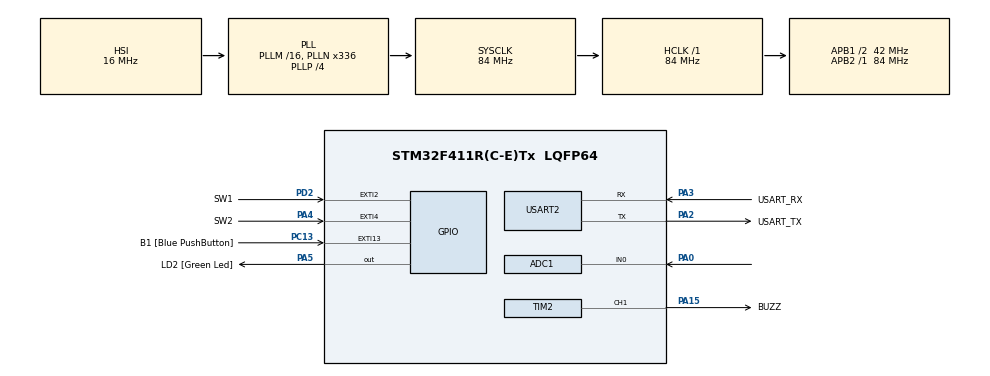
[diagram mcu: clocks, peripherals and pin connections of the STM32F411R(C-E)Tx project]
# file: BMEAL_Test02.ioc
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ADC1.Channel-3\#ChannelRegularConversion=ADC_CHANNEL_0
ADC1.Channel-5\#ChannelRegularConversion=ADC_CHANNEL_TEMPSENSOR
ADC1.EnableAnalogWatchDog=false
ADC1.NbrOfConversion=2
ADC1.NbrOfConversionFlag=1
ADC1.Rank-3\#ChannelRegularConversion=1
ADC1.Rank-5\#ChannelRegularConversion=2
ADC1.SamplingTime-3\#ChannelRegularConversion=ADC_SAMPLETIME_112CYCLES
ADC1.SamplingTime-5\#ChannelRegularConversion=ADC_SAMPLETIME_112CYCLES
ADC1.ScanConvMode=ENABLE
ADC1.master=1
Mcu.Family=STM32F4
Mcu.Name=STM32F411R(C-E)Tx
Mcu.Package=LQFP64
NVIC.EXTI2_IRQn=true\:0\:0\:false\:false\:true\:true\:true\:true
NVIC.EXTI4_IRQn=true\:0\:0\:false\:false\:true\:true\:true\:true
NVIC.PriorityGroup=NVIC_PRIORITYGROUP_0
PA0-WKUP.Signal=ADCx_IN0
PA13.GPIO_Label=TMS
PA13.Mode=Serial_Wire
PA13.Signal=SYS_JTMS-SWDIO
PA14.GPIO_Label=TCK
PA14.Mode=Serial_Wire
PA14.Signal=SYS_JTCK-SWCLK
PA15.GPIO_Label=BUZZ
PA15.Signal=S_TIM2_CH1_ETR
PA2.GPIO_Label=USART_TX
PA2.Mode=Asynchronous
PA2.Signal=USART2_TX
PA3.GPIO_Label=USART_RX
PA3.Mode=Asynchronous
PA3.Signal=USART2_RX
PA4.GPIO_Label=SW2
PA4.GPIO_ModeDefaultEXTI=GPIO_MODE_IT_FALLING
PA4.Signal=GPXTI4
PA5.GPIO_Label=LD2 [Green Led]
PA5.Signal=GPIO_Output
PB3.GPIO_Label=SWO
PB3.Signal=SYS_JTDO-SWO
PC13-ANTI_TAMP.GPIO_Label=B1 [Blue PushButton]
PC13-ANTI_TAMP.GPIO_ModeDefaultEXTI=GPIO_MODE_IT_FALLING
PC13-ANTI_TAMP.Signal=GPXTI13
PC14-OSC32_IN.Mode=LSE-External-Oscillator
PC14-OSC32_IN.Signal=RCC_OSC32_IN
PC15-OSC32_OUT.Mode=LSE-External-Oscillator
PC15-OSC32_OUT.Signal=RCC_OSC32_OUT
PD2.GPIO_Label=SW1
PD2.GPIO_ModeDefaultEXTI=GPIO_MODE_IT_FALLING
PD2.Signal=GPXTI2
PH0\ -\ OSC_IN.Signal=RCC_OSC_IN
PH1\ -\ OSC_OUT.Signal=RCC_OSC_OUT
ProjectManager.HeapSize=0x200
ProjectManager.StackSize=0x400
ProjectManager.TargetToolchain=STM32CubeIDE
RCC.48MHZClocksFreq_Value=84000000
RCC.AHBFreq_Value=84000000
RCC.APB1CLKDivider=RCC_HCLK_DIV2
RCC.APB1Freq_Value=42000000
RCC.APB1TimFreq_Value=84000000
RCC.APB2Freq_Value=84000000
RCC.APB2TimFreq_Value=84000000
RCC.CortexFreq_Value=84000000
RCC.FLatency-AdvancedSettings=FLASH_LATENCY_2
RCC.HCLKFreq_Value=84000000
RCC.HSE_VALUE=8000000
RCC.HSI_VALUE=16000000
RCC.PLLN=336
RCC.PLLP=RCC_PLLP_DIV4
RCC.RCC_RTC_Clock_Source=RCC_RTCCLKSOURCE_LSE
RCC.RCC_RTC_Clock_SourceVirtual=RCC_RTCCLKSOURCE_LSE
RCC.SYSCLKFreq_VALUE=84000000
RCC.SYSCLKSource=RCC_SYSCLKSOURCE_PLLCLK
RCC.VCOOutputFreq_Value=336000000
RTC.Date=30
RTC.Hours=23
RTC.Minutes=59
RTC.Month=RTC_MONTH_OCTOBER
RTC.Seconds=50
RTC.Year=23
SH.ADCx_IN0.0=ADC1_IN0,IN0
SH.S_TIM2_CH1_ETR.0=TIM2_CH1,PWM Generation1 CH1
TIM2.Channel-PWM\ Generation1\ CH1=TIM_CHANNEL_1
TIM2.Period=999
TIM2.Prescaler=83
TIM2.Pulse-PWM\ Generation1\ CH1=499
USART2.VirtualMode=VM_ASYNC
VP_ADC1_TempSens_Input.Mode=IN-TempSens
VP_RTC_VS_RTC_Activate.Mode=RTC_Enabled
VP_RTC_VS_RTC_Calendar.Mode=RTC_Calendar
VP_TIM2_VS_ClockSourceINT.Mode=Internal
board=NUCLEO-F411RE

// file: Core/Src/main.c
/* USER CODE BEGIN Header */
/**
  ******************************************************************************
  * @file           : main.c
  * @brief          : Main program body
  ******************************************************************************
  * @attention
  *
  * Copyright (c) 2023 STMicroelectronics.
  * All rights reserved.
  *
  * This software is licensed under terms that can be found in the LICENSE file
  * in the root directory of this software component.
  * If no LICENSE file comes with this software, it is provided AS-IS.
  *
  ******************************************************************************
  */
/* USER CODE END Header */
#include "main.h"

/* USER CODE BEGIN Includes */

#include <stdio.h>
#include <math.h>

/* USER CODE END Includes */

ADC_HandleTypeDef hadc1;

RTC_HandleTypeDef hrtc;

TIM_HandleTypeDef htim2;

UART_HandleTypeDef huart2;

/* USER CODE BEGIN PV */

uint32_t SysTicks = 0;

const float AVG_SLOPE = 2.5E-03;      // slope (gradient) of temperature line function
const float V25 = 0.76;               // sensor's voltage at 25°C [V]
const float ADC_TO_VOLT = 3.3 / 4096; // conversion coefficient of digital value to volt
                                      // when using 3.3V ref. voltage at 12-bit resolution

char showTime[30] = {0};
char showDate[30] = {0};

uint16_t SWFlag;

/* USER CODE END PV */

void SystemClock_Config(void);
static void MX_GPIO_Init(void);
static void MX_USART2_UART_Init(void);
static void MX_ADC1_Init(void);
static void MX_RTC_Init(void);
static void MX_TIM2_Init(void);
/* USER CODE BEGIN PFP */

void get_time(void);

/* USER CODE END PFP */

/* USER CODE BEGIN 0 */

#ifdef __GNUC__
/* With GCC, small printf (option LD Linker->Libraries->Small printf
   set to 'Yes') calls __io_putchar() */
#define PUTCHAR_PROTOTYPE int __io_putchar(int ch)
#else
#define PUTCHAR_PROTOTYPE int fputc(int ch, FILE *f)
#endif /* __GNUC__ */

/**
  * @brief  Retargets the C library printf function to the USART.
  * @param  None
  * @retval None
  */

PUTCHAR_PROTOTYPE
{
  /* Place your implementation of fputc here */
  /* e.g. write a character to the USART1 and Loop until the end of transmission */
  if (ch == '\n')
    HAL_UART_Transmit (&huart2, (uint8_t*) "\r", 1, 0xFFFF);
  HAL_UART_Transmit (&huart2, (uint8_t*) &ch, 1, 0xFFFF);

  return ch;

}

/* USER CODE END 0 */

int main(void)
{
  /* USER CODE BEGIN 1 */
  uint16_t adc_value[2];
  float my_Temp;
  float vSense;

  /* USER CODE END 1 */

  /* MCU Configuration--------------------------------------------------------*/

  /* Reset of all peripherals, Initializes the Flash interface and the Systick. */
  HAL_Init();

  /* Configure the system clock */
  SystemClock_Config();

  /* Initialize all configured peripherals */
  MX_GPIO_Init();
  MX_USART2_UART_Init();
  MX_ADC1_Init();
  MX_RTC_Init();
  MX_TIM2_Init();

  /* Infinite loop */
  /* USER CODE BEGIN WHILE */
  SWFlag=0;

  while (1)
  {
	  get_time(); // Read RTC Calendar data

	  HAL_ADC_Start(&hadc1);
	  HAL_ADC_PollForConversion(&hadc1, HAL_MAX_DELAY);
	  adc_value[0] = HAL_ADC_GetValue(&hadc1);

	  HAL_ADC_Start(&hadc1);
	  HAL_ADC_PollForConversion(&hadc1, HAL_MAX_DELAY);
	  adc_value[1] = HAL_ADC_GetValue(&hadc1);

	  vSense = adc_value[1] * ADC_TO_VOLT;
	  my_Temp = (V25 - vSense) / AVG_SLOPE + 25.0;

	  printf("%4d,%.3f\n", adc_value[0], my_Temp);

	  if(SWFlag){
		  HAL_TIM_PWM_Start(&htim2, TIM_CHANNEL_1);
		  HAL_Delay(10);
		  HAL_TIM_PWM_Stop(&htim2, TIM_CHANNEL_1);
	  }

	  HAL_Delay(20);
    /* USER CODE END WHILE */

  }
}

void SystemClock_Config(void)
{
  RCC_OscInitTypeDef RCC_OscInitStruct = {0};
  RCC_ClkInitTypeDef RCC_ClkInitStruct = {0};

  /** Configure the main internal regulator output voltage
  */
  __HAL_RCC_PWR_CLK_ENABLE();
  __HAL_PWR_VOLTAGESCALING_CONFIG(PWR_REGULATOR_VOLTAGE_SCALE1);

  /** Initializes the RCC Oscillators according to the specified parameters
  * in the RCC_OscInitTypeDef structure.
  */
  RCC_OscInitStruct.OscillatorType = RCC_OSCILLATORTYPE_HSI|RCC_OSCILLATORTYPE_LSE;
  RCC_OscInitStruct.LSEState = RCC_LSE_ON;
  RCC_OscInitStruct.HSIState = RCC_HSI_ON;
  RCC_OscInitStruct.HSICalibrationValue = RCC_HSICALIBRATION_DEFAULT;
  RCC_OscInitStruct.PLL.PLLState = RCC_PLL_ON;
  RCC_OscInitStruct.PLL.PLLSource = RCC_PLLSOURCE_HSI;
  RCC_OscInitStruct.PLL.PLLM = 16;
  RCC_OscInitStruct.PLL.PLLN = 336;
  RCC_OscInitStruct.PLL.PLLP = RCC_PLLP_DIV4;
  RCC_OscInitStruct.PLL.PLLQ = 4;
  if (HAL_RCC_OscConfig(&RCC_OscInitStruct) != HAL_OK)
  {
    Error_Handler();
  }

  /** Initializes the CPU, AHB and APB buses clocks
  */
  RCC_ClkInitStruct.ClockType = RCC_CLOCKTYPE_HCLK|RCC_CLOCKTYPE_SYSCLK
                              |RCC_CLOCKTYPE_PCLK1|RCC_CLOCKTYPE_PCLK2;
  RCC_ClkInitStruct.SYSCLKSource = RCC_SYSCLKSOURCE_PLLCLK;
  RCC_ClkInitStruct.AHBCLKDivider = RCC_SYSCLK_DIV1;
  RCC_ClkInitStruct.APB1CLKDivider = RCC_HCLK_DIV2;
  RCC_ClkInitStruct.APB2CLKDivider = RCC_HCLK_DIV1;

  if (HAL_RCC_ClockConfig(&RCC_ClkInitStruct, FLASH_LATENCY_2) != HAL_OK)
  {
    Error_Handler();
  }
}

static void MX_ADC1_Init(void)
{

  ADC_ChannelConfTypeDef sConfig = {0};

  /** Configure the global features of the ADC (Clock, Resolution, Data Alignment and number of conversion)
  */
  hadc1.Instance = ADC1;
  hadc1.Init.ClockPrescaler = ADC_CLOCK_SYNC_PCLK_DIV4;
  hadc1.Init.Resolution = ADC_RESOLUTION_12B;
  hadc1.Init.ScanConvMode = ENABLE;
  hadc1.Init.ContinuousConvMode = DISABLE;
  hadc1.Init.DiscontinuousConvMode = DISABLE;
  hadc1.Init.ExternalTrigConvEdge = ADC_EXTERNALTRIGCONVEDGE_NONE;
  hadc1.Init.ExternalTrigConv = ADC_SOFTWARE_START;
  hadc1.Init.DataAlign = ADC_DATAALIGN_RIGHT;
  hadc1.Init.NbrOfConversion = 2;
  hadc1.Init.DMAContinuousRequests = DISABLE;
  hadc1.Init.EOCSelection = ADC_EOC_SINGLE_CONV;
  if (HAL_ADC_Init(&hadc1) != HAL_OK)
  {
    Error_Handler();
  }

  /** Configure for the selected ADC regular channel its corresponding rank in the sequencer and its sample time.
  */
  sConfig.Channel = ADC_CHANNEL_0;
  sConfig.Rank = 1;
  sConfig.SamplingTime = ADC_SAMPLETIME_112CYCLES;
  if (HAL_ADC_ConfigChannel(&hadc1, &sConfig) != HAL_OK)
  {
    Error_Handler();
  }

  /** Configure for the selected ADC regular channel its corresponding rank in the sequencer and its sample time.
  */
  sConfig.Channel = ADC_CHANNEL_TEMPSENSOR;
  sConfig.Rank = 2;
  if (HAL_ADC_ConfigChannel(&hadc1, &sConfig) != HAL_OK)
  {
    Error_Handler();
  }

}

static void MX_RTC_Init(void)
{

  RTC_TimeTypeDef sTime = {0};
  RTC_DateTypeDef sDate = {0};

  /** Initialize RTC Only
  */
  hrtc.Instance = RTC;
  hrtc.Init.HourFormat = RTC_HOURFORMAT_24;
  hrtc.Init.AsynchPrediv = 127;
  hrtc.Init.SynchPrediv = 255;
  hrtc.Init.OutPut = RTC_OUTPUT_DISABLE;
  hrtc.Init.OutPutPolarity = RTC_OUTPUT_POLARITY_HIGH;
  hrtc.Init.OutPutType = RTC_OUTPUT_TYPE_OPENDRAIN;
  if (HAL_RTC_Init(&hrtc) != HAL_OK)
  {
    Error_Handler();
  }

  /** Initialize RTC and set the Time and Date
  */
  sTime.Hours = 0x0;
  sTime.Minutes = 0x0;
  sTime.Seconds = 0x0;

  if (HAL_RTC_SetTime(&hrtc, &sTime, RTC_FORMAT_BCD) != HAL_OK)
  {
    Error_Handler();
  }
  sDate.WeekDay = RTC_WEEKDAY_MONDAY;
  sDate.Month = RTC_MONTH_JANUARY;
  sDate.Date = 0x1;
  sDate.Year = 0x0;

  if (HAL_RTC_SetDate(&hrtc, &sDate, RTC_FORMAT_BCD) != HAL_OK)
  {
    Error_Handler();
  }

}

static void MX_TIM2_Init(void)
{

  TIM_ClockConfigTypeDef sClockSourceConfig = {0};
  TIM_MasterConfigTypeDef sMasterConfig = {0};
  TIM_OC_InitTypeDef sConfigOC = {0};

  htim2.Instance = TIM2;
  htim2.Init.Prescaler = 84-1;
  htim2.Init.CounterMode = TIM_COUNTERMODE_UP;
  htim2.Init.Period = 1000-1;
  htim2.Init.ClockDivision = TIM_CLOCKDIVISION_DIV1;
  htim2.Init.AutoReloadPreload = TIM_AUTORELOAD_PRELOAD_DISABLE;
  if (HAL_TIM_Base_Init(&htim2) != HAL_OK)
  {
    Error_Handler();
  }
  sClockSourceConfig.ClockSource = TIM_CLOCKSOURCE_INTERNAL;
  if (HAL_TIM_ConfigClockSource(&htim2, &sClockSourceConfig) != HAL_OK)
  {
    Error_Handler();
  }
  if (HAL_TIM_PWM_Init(&htim2) != HAL_OK)
  {
    Error_Handler();
  }
  sMasterConfig.MasterOutputTrigger = TIM_TRGO_RESET;
  sMasterConfig.MasterSlaveMode = TIM_MASTERSLAVEMODE_DISABLE;
  if (HAL_TIMEx_MasterConfigSynchronization(&htim2, &sMasterConfig) != HAL_OK)
  {
    Error_Handler();
  }
  sConfigOC.OCMode = TIM_OCMODE_PWM1;
  sConfigOC.Pulse = 500;
  sConfigOC.OCPolarity = TIM_OCPOLARITY_HIGH;
  sConfigOC.OCFastMode = TIM_OCFAST_DISABLE;
  if (HAL_TIM_PWM_ConfigChannel(&htim2, &sConfigOC, TIM_CHANNEL_1) != HAL_OK)
  {
    Error_Handler();
  }
  HAL_TIM_MspPostInit(&htim2);

}

static void MX_USART2_UART_Init(void)
{

  huart2.Instance = USART2;
  huart2.Init.BaudRate = 115200;
  huart2.Init.WordLength = UART_WORDLENGTH_8B;
  huart2.Init.StopBits = UART_STOPBITS_1;
  huart2.Init.Parity = UART_PARITY_NONE;
  huart2.Init.Mode = UART_MODE_TX_RX;
  huart2.Init.HwFlowCtl = UART_HWCONTROL_NONE;
  huart2.Init.OverSampling = UART_OVERSAMPLING_16;
  if (HAL_UART_Init(&huart2) != HAL_OK)
  {
    Error_Handler();
  }

}

static void MX_GPIO_Init(void)
{

  GPIO_InitTypeDef GPIO_InitStruct = {0};

  /* GPIO Ports Clock Enable */
  __HAL_RCC_GPIOC_CLK_ENABLE();
  __HAL_RCC_GPIOH_CLK_ENABLE();
  __HAL_RCC_GPIOA_CLK_ENABLE();
  __HAL_RCC_GPIOB_CLK_ENABLE();

  /*Configure GPIO pin Output Level */
  HAL_GPIO_WritePin(GPIOC, GPIO_PIN_13, GPIO_PIN_RESET);

  /*Configure GPIO pin Output Level */
  HAL_GPIO_WritePin(GPIOA, GPIO_PIN_10, GPIO_PIN_RESET);

  /*Configure GPIO pin Output Level */
  HAL_GPIO_WritePin(GPIOB, GPIO_PIN_4, GPIO_PIN_RESET);

  /*Configure GPIO pin : PC13 */
  GPIO_InitStruct.Pin = GPIO_PIN_13;
  GPIO_InitStruct.Mode = GPIO_MODE_IT_FALLING;
  GPIO_InitStruct.Pull = GPIO_NOPULL;
  HAL_GPIO_Init(GPIOC, &GPIO_InitStruct);

  /*Configure GPIO pin : PA10 */
  GPIO_InitStruct.Pin = GPIO_PIN_10;
  GPIO_InitStruct.Mode = GPIO_MODE_OUTPUT_PP;
  GPIO_InitStruct.Pull = GPIO_NOPULL;
  GPIO_InitStruct.Speed = GPIO_SPEED_FREQ_LOW;
  HAL_GPIO_Init(GPIOA, &GPIO_InitStruct);

  /*Configure GPIO pin : PB4 */
  GPIO_InitStruct.Pin = GPIO_PIN_4;
  GPIO_InitStruct.Mode = GPIO_MODE_OUTPUT_PP;
  GPIO_InitStruct.Pull = GPIO_NOPULL;
  GPIO_InitStruct.Speed = GPIO_SPEED_FREQ_LOW;
  HAL_GPIO_Init(GPIOB, &GPIO_InitStruct);

  /* EXTI interrupt init*/
  HAL_NVIC_SetPriority(EXTI15_10_IRQn, 0, 0);
  HAL_NVIC_EnableIRQ(EXTI15_10_IRQn);

}

/* USER CODE BEGIN 4 */

void SysTick_CallBack(void) {
    // Your code here. For example:
    HAL_IncTick();
    // Any other periodic tasks can be added here.
}

void get_time(void){
	RTC_DateTypeDef gDate;
	RTC_TimeTypeDef gTime;

	/* Get the RTC current Time */
	HAL_RTC_GetTime(&hrtc, &gTime, RTC_FORMAT_BIN);
	/* Get the RTC current Date */
	HAL_RTC_GetDate(&hrtc, &gDate, RTC_FORMAT_BIN);

	sprintf((char*)showTime, "%02d:%02d:%02d", gTime.Hours, gTime.Minutes, gTime.Seconds);
	sprintf((char*)showDate, "%02d-%02d-%2d", gDate.Date, gDate.Month, 2000 + gDate.Year);
}

/* USER CODE END 4 */

void Error_Handler(void)
{
}

/************************ (C) COPYRIGHT STMicroelectronics *****END OF FILE****/
